VERSION 5.8 ;
BUSBITCHARS "[]" ;
DIVIDERCHAR "/" ;
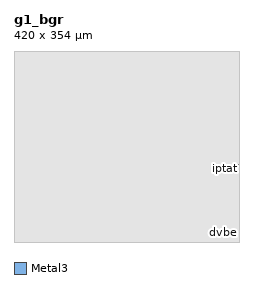
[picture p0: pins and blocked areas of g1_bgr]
MACRO g1_bgr
  CLASS BLOCK ;
  ORIGIN 0 0 ;
  FOREIGN g1_bgr 0 0 ;
  SIZE 420.000 BY 354.000 ;
  SYMMETRY X Y R90 ;
  PIN dvbe
    DIRECTION OUTPUT ;
    USE SIGNAL ;
    PORT
      LAYER Metal3 ;
      RECT 418.500 18.310 419.150 18.610 ;
    END
  END dvbe
  PIN iptat
    DIRECTION OUTPUT ;
    USE SIGNAL ;
    PORT
      LAYER Metal3 ;
      RECT 418.500 136.650 419.150 136.950 ;
    END
  END iptat
  PIN pbias
    DIRECTION OUTPUT ;
    USE SIGNAL ;
    PORT
      LAYER Metal3 ;
      RECT 418.500 138.450 419.150 138.750 ;
    END
  END pbias
  PIN pcasc
    DIRECTION OUTPUT ;
    USE SIGNAL ;
    PORT
      LAYER Metal3 ;
      RECT 418.500 139.050 419.150 139.350 ;
    END
  END pcasc
  PIN r4
    DIRECTION INPUT ;
    USE SIGNAL ;
    PORT
      LAYER Metal3 ;
      RECT 418.500 139.650 419.150 139.950 ;
    END
  END r4
  PIN vbe
    DIRECTION OUTPUT ;
    USE SIGNAL ;
    PORT
      LAYER Metal3 ;
      RECT 418.500 141.450 419.150 141.750 ;
    END
  END vbe
  PIN vdd
    DIRECTION INOUT ;
    USE POWER ;
    PORT
      LAYER Metal3 ;
      RECT 418.500 142.050 419.150 142.350 ;
    END
  END vdd
  PIN vref
    DIRECTION OUTPUT ;
    USE SIGNAL ;
    PORT
      LAYER Metal3 ;
      RECT 418.500 142.650 419.150 142.950 ;
    END
  END vref
  PIN vss
    DIRECTION INOUT ;
    USE GROUND ;
    PORT
      LAYER Metal3 ;
      RECT 418.500 143.250 419.150 143.550 ;
    END
  END vss
  OBS
    LAYER Metal1 ;
      RECT 0.000 0.000 420.000 354.000 ;
    LAYER Metal2 ;
      RECT 0.000 0.000 420.000 354.000 ;
    LAYER Metal3 ;
      RECT 0.000 0.000 420.000 17.810 ;
      RECT 0.000 17.810 418.500 19.110 ;
      RECT 0.000 19.110 420.000 136.150 ;
      RECT 0.000 136.150 419.150 136.350 ;
      RECT 0.000 136.350 418.500 137.250 ;
      RECT 0.000 137.250 419.150 137.450 ;
      RECT 0.000 137.450 420.000 137.950 ;
      RECT 0.000 137.950 419.150 138.150 ;
      RECT 0.000 138.150 418.500 140.250 ;
      RECT 0.000 140.250 419.150 140.450 ;
      RECT 0.000 140.450 420.000 140.950 ;
      RECT 0.000 140.950 419.150 141.150 ;
      RECT 0.000 141.150 418.500 144.050 ;
      RECT 0.000 144.050 420.000 354.000 ;
    LAYER Metal4 ;
      RECT 0.000 0.000 420.000 354.000 ;
    LAYER Metal5 ;
      RECT 0.000 0.000 420.000 354.000 ;
  END
END g1_bgr
END LIBRARY
